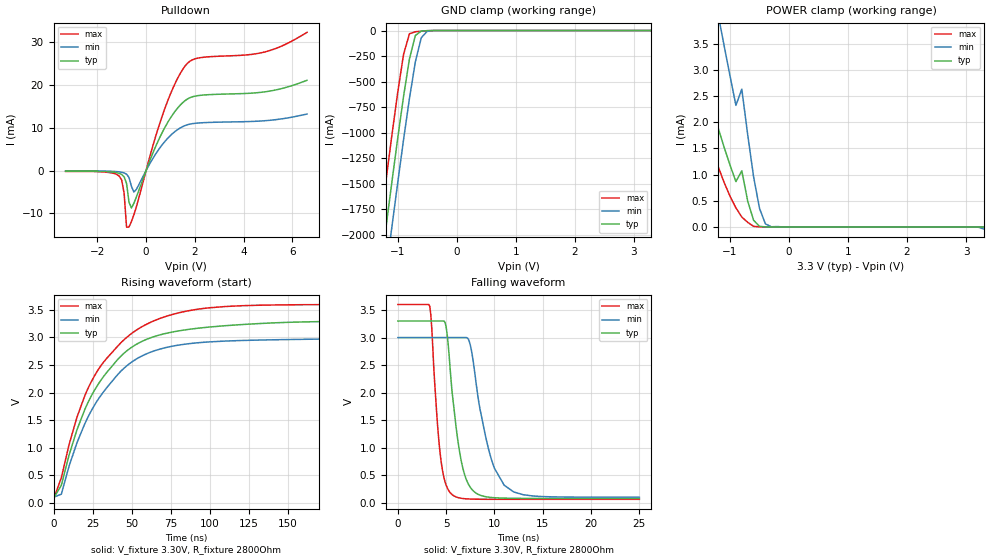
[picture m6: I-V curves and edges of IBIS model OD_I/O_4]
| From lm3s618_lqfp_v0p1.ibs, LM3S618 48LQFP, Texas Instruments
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[Model]   OD_I/O_4
Model_type   I/O_open_drain
Polarity   Inverting
Vinl = 1.26
Vinh = 2.04
Vmeas = 1.65
Rref = 2800
Vref = 3.3
| variable   typ   min   max
C_comp   9.739pF   9.739pF   9.739pF
[Model Spec]
Vinh+   1.91   1.78   2.04
Vinh-   1.90   1.76   2.03
Vinl+   1.40   1.27   1.54
Vinl-   1.39   1.26   1.53
| variable   typ   min   max
[Temperature Range]  25   85   -40
[Voltage Range]   3.3V   3.0V   3.6V
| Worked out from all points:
|   slope of the pulldown table from 0 to 0.495 V, typ, clamps not added: 71.5 ohm
|   GND clamp passes 1 mA (typ) near -0.48 V on its own axis
|   POWER clamp passes 1 mA (typ) near -0.79 V on its own axis
|   falling waveform, V_fixture 3.30V, R_fixture 2800Ohm: 20-80 % time 1.29ns typ, 1.97ns min, 871ps max; typ from 3.3 V to 0.075 V
|   rising waveform, V_fixture 3.30V, R_fixture 2800Ohm: 20-80 % time 34.2ns typ, 34ns min, 35.1ns max; typ from 0.075 V to 3.3 V
[Pulldown]
|  Voltage   I(typ)   I(min)   I(max)
-3.3V     -128.3uA   -72.81uA   -182.3uA
-1.1V     -636.5uA   -293.8uA   -1.284mA
-900mV    -1.443mA   -530.4uA   -5.27mA
-800mV    -2.996mA   -835.1uA   -13.2mA
-700mV    -7.355mA   -1.607mA   -13.16mA
-600mV    -8.716mA   -3.66mA    -11.87mA
-500mV    -7.628mA   -5mA       -10.33mA
700mV     9.309mA    6.304mA    13.37mA
1.2V      13.92mA    9.18mA     20.46mA
1.7V      16.72mA    10.71mA    25.07mA
4.9V      18.4mA     11.65mA    27.73mA
6.6V      21.07mA    13.21mA    32.27mA
[GND Clamp]
|  Voltage   I(typ)   I(min)   I(max)
-3.3V     -11.72A    -12.12A    -11.3A
-1.4V     -2.845A    -3.285A    -2.387A
-1.3V     -2.39A     -2.831A    -1.93A
-1.2V     -1.938A    -2.38A     -1.478A
-1.1V     -1.494A    -1.934A    -1.036A
-1V       -1.059A    -1.496A    -610.6mA
-900mV    -645mA     -1.069A    -232.9mA
-800mV    -277.1mA   -664.4mA   -31.59mA
-700mV    -48.56mA   -306.6mA   -12.09mA
-600mV    -5.558mA   -70.2mA    -6.272mA
-500mV    -1.167mA   -7.879mA   -2.167mA
3.3V      2.282nA    3.101uA    451.3pA
[POWER Clamp]
|  Voltage   I(typ)   I(min)   I(max)
-3.3V     12.41mA    17.26mA    12.22mA
-1.9V     4.919mA    8.328mA    4.074mA
-1.8V     4.445mA    7.705mA    3.587mA
-1.6V     3.533mA    6.47mA     2.675mA
-1.2V     1.89mA     4.055mA    1.153mA
-1.1V     1.526mA    3.468mA    851.4uA
-900mV    866.3uA    2.324mA    364.9uA
-800mV    1.074mA    2.635mA    188.8uA
-600mV    127.8uA    958.5uA    11.41uA
-500mV    11.24uA    355.9uA    954.7nA
-300mV    9.515nA    3.101uA    1.472nA
3.3V      -104.7pA   -40.34uA   119.2pA
[Ramp]
| variable   typ   min   max
dV/dt_f   1.93/1.29n   1.74/1.97n   2.12/0.87n
dV/dt_r   1.93/34.23n   1.74/34.00n   2.12/35.11n
R_load = 2800Ohm
[Falling Waveform]
V_fixture = 3.30V
V_fixture_min = 3.00V
V_fixture_max = 3.60V
R_fixture = 2800Ohm
|   Time   V(typ)   V(min)   V(max)
0s        3.3V       2.999V     3.6V
3.3ns     3.3V       2.999V     3.563V
4.4ns     3.3V       2.999V     848.4mV
5ns       3.181V     2.999V     313.8mV
5.6ns     2.025V     2.999V     146.2mV
6.4ns     906.7mV    2.999V     82.58mV
7.2ns     370.3mV    2.992V     66.15mV
9.4ns     97.63mV    961.6mV    59.22mV
11ns      79.91mV    315.9mV    58.8mV
25ns      75.03mV    97.59mV    58.6mV
[Rising Waveform]
V_fixture = 3.30V
V_fixture_min = 3.00V
V_fixture_max = 3.60V
R_fixture = 2800Ohm
|   Time   V(typ)   V(min)   V(max)
0s        74.96mV    97.5mV     58.54mV
5ns       314.1mV    152.4mV    452.4mV
10ns      867.1mV    666.7mV    1.059V
15ns      1.323V     1.087V     1.551V
25ns      1.981V     1.71V      2.24V
43ns      2.657V     2.383V     2.9V
60ns      2.971V     2.709V     3.247V
82ns      3.128V     2.87V      3.46V
110ns     3.214V     2.935V     3.563V
250ns     3.298V     2.994V     3.599V
